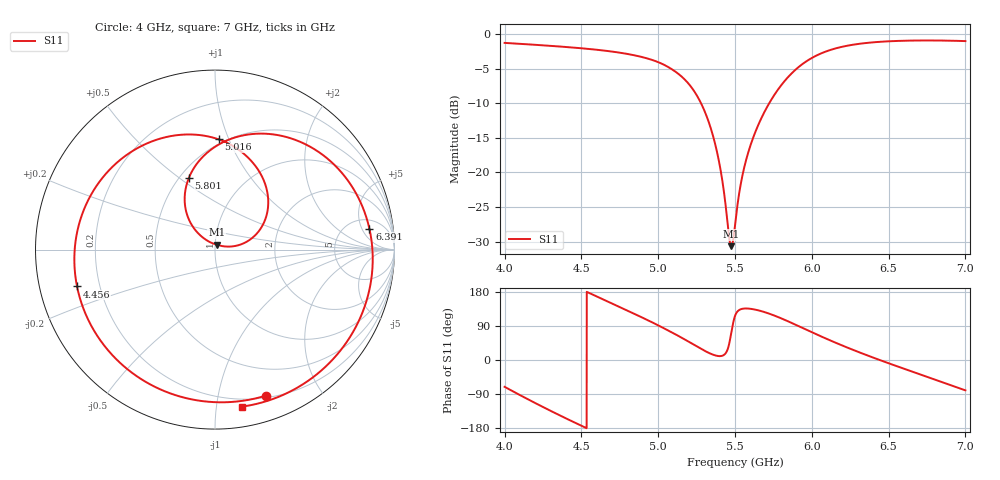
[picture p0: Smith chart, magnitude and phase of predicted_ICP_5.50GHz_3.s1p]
! ICP-predicted S11, target max centred GHz at -10 dB. Complex ensemble mean (passive and causal);
! its |S11| can differ slightly from the dB-domain mean reported in designs.csv.
!  Air_gap = 3.3mm
!  W_Patch = 11.23mm
!  L_Patch = 18.01mm
!  Sx = 1.67mm
!  Sy = 2.84mm
!  W_Patch1 = 11.99mm
!  WS = 1.1mm
!  Curve_Amp1 = 1.47mm
!  Extra = 2.63mm
# GHz S MA R 50
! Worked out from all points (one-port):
!   3001 points, 4 GHz to 7 GHz, reference 50 ohm
!   lowest |S11| = -30.7 dB at 5.475 GHz (marker M1), VSWR 1.06, Z = 50.9 + j2.82 ohm
!   |S11| at or under -10 dB: 5.279 GHz to 5.723 GHz (444.5 MHz wide, 8.08 % of centre)
!   S11 on the Smith chart (normalised r, x): 4 GHz: 0.22, -1.38; 4.456 GHz: 0.12, -0.13; 5.016 GHz: 0.47, +0.92; 5.801 GHz: 0.56, +0.54; 6.391 GHz: 8, +7; 7 GHz: 0.14, -1.18
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4  0.8617 -70.8
4.086  0.8503 -89.6
4.172  0.8385 -107.9
4.375  0.8088 -149.2
4.456  0.7956 -165.1
4.597  0.7693 168.1
4.75  0.7321 139.6
4.888  0.6838 113.6
5.016  0.6147 88.1
5.125  0.5212 65.0
5.231  0.3905 40.6
5.34  0.2121 16.8
5.403  0.1088 10.2
5.461  0.0346 40.8
5.475  0.02928 70.7
5.5  0.04135 116.3
5.543  0.08871 134.7
5.601  0.157 135.1
5.69  0.2709 126.7
5.801  0.4262 109.9
5.875  0.5271 96.7
6.054  0.7181 63.4
6.25  0.8294 29.7
6.391  0.8682 7.6
6.505  0.8853 -9.3
6.625  0.8944 -26.6
6.824  0.8964 -54.8
7  0.8877 -80.2
